VERSION 5.7 ;
  NOWIREEXTENSIONATPIN ON ;
  DIVIDERCHAR "/" ;
  BUSBITCHARS "[]" ;
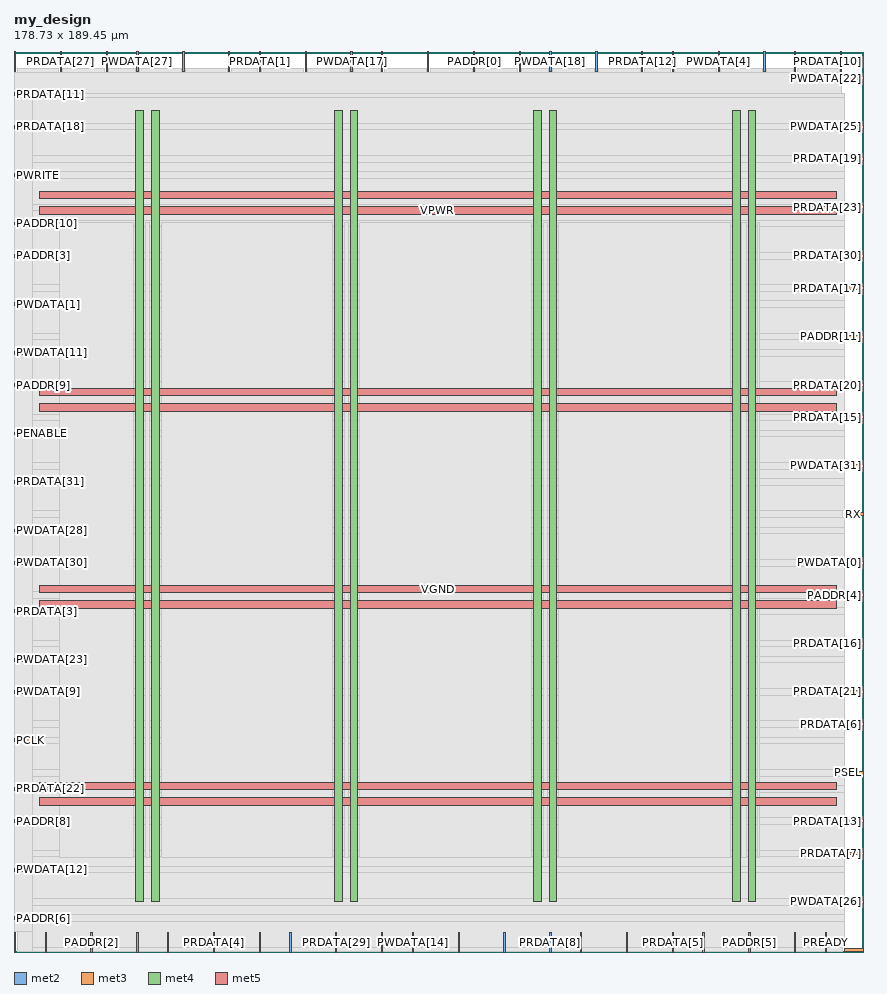
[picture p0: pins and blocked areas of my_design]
MACRO my_design
  CLASS BLOCK ;
  FOREIGN my_design ;
  ORIGIN 0.000 0.000 ;
  SIZE 178.730 BY 189.450 ;
  PIN PADDR[0]
    DIRECTION INPUT ;
    USE SIGNAL ;
    ANTENNAGATEAREA 0.196500 ;
    PORT
      LAYER met2 ;
        RECT 96.690 185.450 96.970 189.450 ;
    END
  END PADDR[0]
  PIN PADDR[10]
    DIRECTION INPUT ;
    USE SIGNAL ;
    ANTENNAGATEAREA 0.196500 ;
    PORT
      LAYER met3 ;
        RECT 0.000 153.040 4.000 153.640 ;
    END
  END PADDR[10]
  PIN PADDR[11]
    DIRECTION INPUT ;
    USE SIGNAL ;
    ANTENNAGATEAREA 0.126000 ;
    PORT
      LAYER met3 ;
        RECT 174.730 129.240 178.730 129.840 ;
    END
  END PADDR[11]
  PIN PADDR[1]
    DIRECTION INPUT ;
    USE SIGNAL ;
    ANTENNAGATEAREA 0.196500 ;
    PORT
      LAYER met2 ;
        RECT 35.510 185.450 35.790 189.450 ;
    END
  END PADDR[1]
  PIN PADDR[2]
    DIRECTION INPUT ;
    USE SIGNAL ;
    ANTENNAGATEAREA 0.159000 ;
    PORT
      LAYER met2 ;
        RECT 16.190 0.000 16.470 4.000 ;
    END
  END PADDR[2]
  PIN PADDR[3]
    DIRECTION INPUT ;
    USE SIGNAL ;
    ANTENNAGATEAREA 0.213000 ;
    PORT
      LAYER met3 ;
        RECT 0.000 146.240 4.000 146.840 ;
    END
  END PADDR[3]
  PIN PADDR[4]
    DIRECTION INPUT ;
    USE SIGNAL ;
    ANTENNAGATEAREA 0.196500 ;
    PORT
      LAYER met3 ;
        RECT 174.730 74.840 178.730 75.440 ;
    END
  END PADDR[4]
  PIN PADDR[5]
    DIRECTION INPUT ;
    USE SIGNAL ;
    ANTENNAGATEAREA 0.196500 ;
    PORT
      LAYER met2 ;
        RECT 154.650 0.000 154.930 4.000 ;
    END
  END PADDR[5]
  PIN PADDR[6]
    DIRECTION INPUT ;
    USE SIGNAL ;
    ANTENNAGATEAREA 0.196500 ;
    PORT
      LAYER met3 ;
        RECT 0.000 6.840 4.000 7.440 ;
    END
  END PADDR[6]
  PIN PADDR[7]
    DIRECTION INPUT ;
    USE SIGNAL ;
    ANTENNAGATEAREA 0.196500 ;
    PORT
      LAYER met2 ;
        RECT 144.990 0.000 145.270 4.000 ;
    END
  END PADDR[7]
  PIN PADDR[8]
    DIRECTION INPUT ;
    USE SIGNAL ;
    ANTENNAGATEAREA 0.196500 ;
    PORT
      LAYER met3 ;
        RECT 0.000 27.240 4.000 27.840 ;
    END
  END PADDR[8]
  PIN PADDR[9]
    DIRECTION INPUT ;
    USE SIGNAL ;
    ANTENNAGATEAREA 0.196500 ;
    PORT
      LAYER met3 ;
        RECT 0.000 119.040 4.000 119.640 ;
    END
  END PADDR[9]
  PIN PCLK
    DIRECTION INPUT ;
    USE SIGNAL ;
    ANTENNAGATEAREA 0.852000 ;
    PORT
      LAYER met3 ;
        RECT 0.000 44.240 4.000 44.840 ;
    END
  END PCLK
  PIN PENABLE
    DIRECTION INPUT ;
    USE SIGNAL ;
    ANTENNAGATEAREA 0.196500 ;
    PORT
      LAYER met3 ;
        RECT 0.000 108.840 4.000 109.440 ;
    END
  END PENABLE
  PIN PRDATA[0]
    DIRECTION OUTPUT TRISTATE ;
    USE SIGNAL ;
    ANTENNADIFFAREA 0.795200 ;
    PORT
      LAYER met3 ;
        RECT 174.730 0.040 178.730 0.640 ;
    END
  END PRDATA[0]
  PIN PRDATA[10]
    DIRECTION OUTPUT TRISTATE ;
    USE SIGNAL ;
    ANTENNADIFFAREA 0.795200 ;
    PORT
      LAYER met2 ;
        RECT 173.970 185.450 174.250 189.450 ;
    END
  END PRDATA[10]
  PIN PRDATA[11]
    DIRECTION OUTPUT TRISTATE ;
    USE SIGNAL ;
    ANTENNADIFFAREA 0.795200 ;
    PORT
      LAYER met3 ;
        RECT 0.000 180.240 4.000 180.840 ;
    END
  END PRDATA[11]
  PIN PRDATA[12]
    DIRECTION OUTPUT TRISTATE ;
    USE SIGNAL ;
    ANTENNADIFFAREA 0.795200 ;
    PORT
      LAYER met2 ;
        RECT 132.110 185.450 132.390 189.450 ;
    END
  END PRDATA[12]
  PIN PRDATA[13]
    DIRECTION OUTPUT TRISTATE ;
    USE SIGNAL ;
    ANTENNADIFFAREA 0.795200 ;
    PORT
      LAYER met3 ;
        RECT 174.730 27.240 178.730 27.840 ;
    END
  END PRDATA[13]
  PIN PRDATA[14]
    DIRECTION OUTPUT TRISTATE ;
    USE SIGNAL ;
    ANTENNADIFFAREA 0.795200 ;
    PORT
      LAYER met2 ;
        RECT 87.030 185.450 87.310 189.450 ;
    END
  END PRDATA[14]
  PIN PRDATA[15]
    DIRECTION OUTPUT TRISTATE ;
    USE SIGNAL ;
    ANTENNADIFFAREA 0.445500 ;
    PORT
      LAYER met3 ;
        RECT 174.730 112.240 178.730 112.840 ;
    END
  END PRDATA[15]
  PIN PRDATA[16]
    DIRECTION OUTPUT TRISTATE ;
    USE SIGNAL ;
    ANTENNADIFFAREA 0.445500 ;
    PORT
      LAYER met3 ;
        RECT 174.730 64.640 178.730 65.240 ;
    END
  END PRDATA[16]
  PIN PRDATA[17]
    DIRECTION OUTPUT TRISTATE ;
    USE SIGNAL ;
    PORT
      LAYER met3 ;
        RECT 174.730 139.440 178.730 140.040 ;
    END
  END PRDATA[17]
  PIN PRDATA[18]
    DIRECTION OUTPUT TRISTATE ;
    USE SIGNAL ;
    ANTENNADIFFAREA 0.795200 ;
    PORT
      LAYER met3 ;
        RECT 0.000 173.440 4.000 174.040 ;
    END
  END PRDATA[18]
  PIN PRDATA[19]
    DIRECTION OUTPUT TRISTATE ;
    USE SIGNAL ;
    ANTENNADIFFAREA 0.445500 ;
    PORT
      LAYER met3 ;
        RECT 174.730 166.640 178.730 167.240 ;
    END
  END PRDATA[19]
  PIN PRDATA[1]
    DIRECTION OUTPUT TRISTATE ;
    USE SIGNAL ;
    ANTENNADIFFAREA 0.795200 ;
    PORT
      LAYER met2 ;
        RECT 51.610 185.450 51.890 189.450 ;
    END
  END PRDATA[1]
  PIN PRDATA[20]
    DIRECTION OUTPUT TRISTATE ;
    USE SIGNAL ;
    PORT
      LAYER met3 ;
        RECT 174.730 119.040 178.730 119.640 ;
    END
  END PRDATA[20]
  PIN PRDATA[21]
    DIRECTION OUTPUT TRISTATE ;
    USE SIGNAL ;
    ANTENNADIFFAREA 0.795200 ;
    PORT
      LAYER met3 ;
        RECT 174.730 54.440 178.730 55.040 ;
    END
  END PRDATA[21]
  PIN PRDATA[22]
    DIRECTION OUTPUT TRISTATE ;
    USE SIGNAL ;
    PORT
      LAYER met3 ;
        RECT 0.000 34.040 4.000 34.640 ;
    END
  END PRDATA[22]
  PIN PRDATA[23]
    DIRECTION OUTPUT TRISTATE ;
    USE SIGNAL ;
    ANTENNADIFFAREA 0.795200 ;
    PORT
      LAYER met3 ;
        RECT 174.730 156.440 178.730 157.040 ;
    END
  END PRDATA[23]
  PIN PRDATA[24]
    DIRECTION OUTPUT TRISTATE ;
    USE SIGNAL ;
    PORT
      LAYER met2 ;
        RECT 51.610 0.000 51.890 4.000 ;
    END
  END PRDATA[24]
  PIN PRDATA[25]
    DIRECTION OUTPUT TRISTATE ;
    USE SIGNAL ;
    ANTENNADIFFAREA 0.795200 ;
    PORT
      LAYER met2 ;
        RECT 164.310 0.000 164.590 4.000 ;
    END
  END PRDATA[25]
  PIN PRDATA[26]
    DIRECTION OUTPUT TRISTATE ;
    USE SIGNAL ;
    ANTENNADIFFAREA 0.795200 ;
    PORT
      LAYER met2 ;
        RECT 122.450 185.450 122.730 189.450 ;
    END
  END PRDATA[26]
  PIN PRDATA[27]
    DIRECTION OUTPUT TRISTATE ;
    USE SIGNAL ;
    ANTENNADIFFAREA 0.795200 ;
    PORT
      LAYER met2 ;
        RECT 9.750 185.450 10.030 189.450 ;
    END
  END PRDATA[27]
  PIN PRDATA[28]
    DIRECTION OUTPUT TRISTATE ;
    USE SIGNAL ;
    ANTENNADIFFAREA 0.795200 ;
    PORT
      LAYER met2 ;
        RECT 106.350 185.450 106.630 189.450 ;
    END
  END PRDATA[28]
  PIN PRDATA[29]
    DIRECTION OUTPUT TRISTATE ;
    USE SIGNAL ;
    PORT
      LAYER met2 ;
        RECT 67.710 0.000 67.990 4.000 ;
    END
  END PRDATA[29]
  PIN PRDATA[2]
    DIRECTION OUTPUT TRISTATE ;
    USE SIGNAL ;
    ANTENNADIFFAREA 0.795200 ;
    PORT
      LAYER met2 ;
        RECT 157.870 185.450 158.150 189.450 ;
    END
  END PRDATA[2]
  PIN PRDATA[30]
    DIRECTION OUTPUT TRISTATE ;
    USE SIGNAL ;
    ANTENNADIFFAREA 0.445500 ;
    PORT
      LAYER met3 ;
        RECT 174.730 146.240 178.730 146.840 ;
    END
  END PRDATA[30]
  PIN PRDATA[31]
    DIRECTION OUTPUT TRISTATE ;
    USE SIGNAL ;
    ANTENNADIFFAREA 0.795200 ;
    PORT
      LAYER met3 ;
        RECT 0.000 98.640 4.000 99.240 ;
    END
  END PRDATA[31]
  PIN PRDATA[3]
    DIRECTION OUTPUT TRISTATE ;
    USE SIGNAL ;
    ANTENNADIFFAREA 0.795200 ;
    PORT
      LAYER met3 ;
        RECT 0.000 71.440 4.000 72.040 ;
    END
  END PRDATA[3]
  PIN PRDATA[4]
    DIRECTION OUTPUT TRISTATE ;
    USE SIGNAL ;
    ANTENNADIFFAREA 0.795200 ;
    PORT
      LAYER met2 ;
        RECT 41.950 0.000 42.230 4.000 ;
    END
  END PRDATA[4]
  PIN PRDATA[5]
    DIRECTION OUTPUT TRISTATE ;
    USE SIGNAL ;
    ANTENNADIFFAREA 0.795200 ;
    PORT
      LAYER met2 ;
        RECT 138.550 0.000 138.830 4.000 ;
    END
  END PRDATA[5]
  PIN PRDATA[6]
    DIRECTION OUTPUT TRISTATE ;
    USE SIGNAL ;
    ANTENNADIFFAREA 0.795200 ;
    PORT
      LAYER met3 ;
        RECT 174.730 47.640 178.730 48.240 ;
    END
  END PRDATA[6]
  PIN PRDATA[7]
    DIRECTION OUTPUT TRISTATE ;
    USE SIGNAL ;
    ANTENNADIFFAREA 0.795200 ;
    PORT
      LAYER met3 ;
        RECT 174.730 20.440 178.730 21.040 ;
    END
  END PRDATA[7]
  PIN PRDATA[8]
    DIRECTION OUTPUT TRISTATE ;
    USE SIGNAL ;
    ANTENNADIFFAREA 0.795200 ;
    PORT
      LAYER met2 ;
        RECT 112.790 0.000 113.070 4.000 ;
    END
  END PRDATA[8]
  PIN PRDATA[9]
    DIRECTION OUTPUT TRISTATE ;
    USE SIGNAL ;
    ANTENNADIFFAREA 0.795200 ;
    PORT
      LAYER met2 ;
        RECT 0.090 185.450 0.370 189.450 ;
    END
  END PRDATA[9]
  PIN PREADY
    DIRECTION OUTPUT TRISTATE ;
    USE SIGNAL ;
    ANTENNADIFFAREA 0.795200 ;
    PORT
      LAYER met2 ;
        RECT 170.750 0.000 171.030 4.000 ;
    END
  END PREADY
  PIN PRESETn
    DIRECTION INPUT ;
    USE SIGNAL ;
    ANTENNAGATEAREA 0.196500 ;
    PORT
      LAYER met2 ;
        RECT 61.270 185.450 61.550 189.450 ;
    END
  END PRESETn
  PIN PSEL
    DIRECTION INPUT ;
    USE SIGNAL ;
    ANTENNAGATEAREA 0.159000 ;
    PORT
      LAYER met3 ;
        RECT 174.730 37.440 178.730 38.040 ;
    END
  END PSEL
  PIN PWDATA[0]
    DIRECTION INPUT ;
    USE SIGNAL ;
    ANTENNAGATEAREA 0.213000 ;
    PORT
      LAYER met3 ;
        RECT 174.730 81.640 178.730 82.240 ;
    END
  END PWDATA[0]
  PIN PWDATA[10]
    DIRECTION INPUT ;
    USE SIGNAL ;
    ANTENNAGATEAREA 0.126000 ;
    PORT
      LAYER met2 ;
        RECT 128.890 0.000 129.170 4.000 ;
    END
  END PWDATA[10]
  PIN PWDATA[11]
    DIRECTION INPUT ;
    USE SIGNAL ;
    ANTENNAGATEAREA 0.196500 ;
    PORT
      LAYER met3 ;
        RECT 0.000 125.840 4.000 126.440 ;
    END
  END PWDATA[11]
  PIN PWDATA[12]
    DIRECTION INPUT ;
    USE SIGNAL ;
    ANTENNAGATEAREA 0.196500 ;
    PORT
      LAYER met3 ;
        RECT 0.000 17.040 4.000 17.640 ;
    END
  END PWDATA[12]
  PIN PWDATA[13]
    DIRECTION INPUT ;
    USE SIGNAL ;
    ANTENNAGATEAREA 0.196500 ;
    PORT
      LAYER met2 ;
        RECT 77.370 185.450 77.650 189.450 ;
    END
  END PWDATA[13]
  PIN PWDATA[14]
    DIRECTION INPUT ;
    USE SIGNAL ;
    ANTENNAGATEAREA 0.196500 ;
    PORT
      LAYER met2 ;
        RECT 83.810 0.000 84.090 4.000 ;
    END
  END PWDATA[14]
  PIN PWDATA[15]
    DIRECTION INPUT ;
    USE SIGNAL ;
    ANTENNAGATEAREA 0.196500 ;
    PORT
      LAYER met2 ;
        RECT 0.090 0.000 0.370 4.000 ;
    END
  END PWDATA[15]
  PIN PWDATA[16]
    DIRECTION INPUT ;
    USE SIGNAL ;
    PORT
      LAYER met2 ;
        RECT 103.130 0.000 103.410 4.000 ;
    END
  END PWDATA[16]
  PIN PWDATA[17]
    DIRECTION INPUT ;
    USE SIGNAL ;
    PORT
      LAYER met2 ;
        RECT 70.930 185.450 71.210 189.450 ;
    END
  END PWDATA[17]
  PIN PWDATA[18]
    DIRECTION INPUT ;
    USE SIGNAL ;
    PORT
      LAYER met2 ;
        RECT 112.790 185.450 113.070 189.450 ;
    END
  END PWDATA[18]
  PIN PWDATA[19]
    DIRECTION INPUT ;
    USE SIGNAL ;
    PORT
      LAYER met2 ;
        RECT 164.310 185.450 164.590 189.450 ;
    END
  END PWDATA[19]
  PIN PWDATA[1]
    DIRECTION INPUT ;
    USE SIGNAL ;
    ANTENNAGATEAREA 0.196500 ;
    PORT
      LAYER met3 ;
        RECT 0.000 136.040 4.000 136.640 ;
    END
  END PWDATA[1]
  PIN PWDATA[20]
    DIRECTION INPUT ;
    USE SIGNAL ;
    PORT
      LAYER met2 ;
        RECT 25.850 0.000 26.130 4.000 ;
    END
  END PWDATA[20]
  PIN PWDATA[21]
    DIRECTION INPUT ;
    USE SIGNAL ;
    PORT
      LAYER met2 ;
        RECT 6.530 0.000 6.810 4.000 ;
    END
  END PWDATA[21]
  PIN PWDATA[22]
    DIRECTION INPUT ;
    USE SIGNAL ;
    PORT
      LAYER met3 ;
        RECT 174.730 183.640 178.730 184.240 ;
    END
  END PWDATA[22]
  PIN PWDATA[23]
    DIRECTION INPUT ;
    USE SIGNAL ;
    PORT
      LAYER met3 ;
        RECT 0.000 61.240 4.000 61.840 ;
    END
  END PWDATA[23]
  PIN PWDATA[24]
    DIRECTION INPUT ;
    USE SIGNAL ;
    PORT
      LAYER met2 ;
        RECT 77.370 0.000 77.650 4.000 ;
    END
  END PWDATA[24]
  PIN PWDATA[25]
    DIRECTION INPUT ;
    USE SIGNAL ;
    PORT
      LAYER met3 ;
        RECT 174.730 173.440 178.730 174.040 ;
    END
  END PWDATA[25]
  PIN PWDATA[26]
    DIRECTION INPUT ;
    USE SIGNAL ;
    PORT
      LAYER met3 ;
        RECT 174.730 10.240 178.730 10.840 ;
    END
  END PWDATA[26]
  PIN PWDATA[27]
    DIRECTION INPUT ;
    USE SIGNAL ;
    PORT
      LAYER met2 ;
        RECT 25.850 185.450 26.130 189.450 ;
    END
  END PWDATA[27]
  PIN PWDATA[28]
    DIRECTION INPUT ;
    USE SIGNAL ;
    PORT
      LAYER met3 ;
        RECT 0.000 88.440 4.000 89.040 ;
    END
  END PWDATA[28]
  PIN PWDATA[29]
    DIRECTION INPUT ;
    USE SIGNAL ;
    PORT
      LAYER met2 ;
        RECT 32.290 0.000 32.570 4.000 ;
    END
  END PWDATA[29]
  PIN PWDATA[2]
    DIRECTION INPUT ;
    USE SIGNAL ;
    ANTENNAGATEAREA 0.196500 ;
    PORT
      LAYER met2 ;
        RECT 58.050 0.000 58.330 4.000 ;
    END
  END PWDATA[2]
  PIN PWDATA[30]
    DIRECTION INPUT ;
    USE SIGNAL ;
    PORT
      LAYER met3 ;
        RECT 0.000 81.640 4.000 82.240 ;
    END
  END PWDATA[30]
  PIN PWDATA[31]
    DIRECTION INPUT ;
    USE SIGNAL ;
    PORT
      LAYER met3 ;
        RECT 174.730 102.040 178.730 102.640 ;
    END
  END PWDATA[31]
  PIN PWDATA[3]
    DIRECTION INPUT ;
    USE SIGNAL ;
    ANTENNAGATEAREA 0.196500 ;
    PORT
      LAYER met2 ;
        RECT 93.470 0.000 93.750 4.000 ;
    END
  END PWDATA[3]
  PIN PWDATA[4]
    DIRECTION INPUT ;
    USE SIGNAL ;
    ANTENNAGATEAREA 0.196500 ;
    PORT
      LAYER met2 ;
        RECT 148.210 185.450 148.490 189.450 ;
    END
  END PWDATA[4]
  PIN PWDATA[5]
    DIRECTION INPUT ;
    USE SIGNAL ;
    ANTENNAGATEAREA 0.196500 ;
    PORT
      LAYER met2 ;
        RECT 138.550 185.450 138.830 189.450 ;
    END
  END PWDATA[5]
  PIN PWDATA[6]
    DIRECTION INPUT ;
    USE SIGNAL ;
    ANTENNAGATEAREA 0.196500 ;
    PORT
      LAYER met2 ;
        RECT 19.410 185.450 19.690 189.450 ;
    END
  END PWDATA[6]
  PIN PWDATA[7]
    DIRECTION INPUT ;
    USE SIGNAL ;
    ANTENNAGATEAREA 0.196500 ;
    PORT
      LAYER met2 ;
        RECT 45.170 185.450 45.450 189.450 ;
    END
  END PWDATA[7]
  PIN PWDATA[8]
    DIRECTION INPUT ;
    USE SIGNAL ;
    ANTENNAGATEAREA 0.196500 ;
    PORT
      LAYER met2 ;
        RECT 119.230 0.000 119.510 4.000 ;
    END
  END PWDATA[8]
  PIN PWDATA[9]
    DIRECTION INPUT ;
    USE SIGNAL ;
    ANTENNAGATEAREA 0.196500 ;
    PORT
      LAYER met3 ;
        RECT 0.000 54.440 4.000 55.040 ;
    END
  END PWDATA[9]
  PIN PWRITE
    DIRECTION INPUT ;
    USE SIGNAL ;
    ANTENNAGATEAREA 0.126000 ;
    PORT
      LAYER met3 ;
        RECT 0.000 163.240 4.000 163.840 ;
    END
  END PWRITE
  PIN RX
    DIRECTION INPUT ;
    USE SIGNAL ;
    ANTENNAGATEAREA 0.196500 ;
    PORT
      LAYER met3 ;
        RECT 174.730 91.840 178.730 92.440 ;
    END
  END RX
  PIN VGND
    DIRECTION INOUT ;
    USE GROUND ;
    PORT
      LAYER met4 ;
        RECT 28.950 10.640 30.550 177.040 ;
    END
    PORT
      LAYER met4 ;
        RECT 70.810 10.640 72.410 177.040 ;
    END
    PORT
      LAYER met4 ;
        RECT 112.670 10.640 114.270 177.040 ;
    END
    PORT
      LAYER met4 ;
        RECT 154.530 10.640 156.130 177.040 ;
    END
    PORT
      LAYER met5 ;
        RECT 5.280 34.120 173.200 35.720 ;
    END
    PORT
      LAYER met5 ;
        RECT 5.280 75.600 173.200 77.200 ;
    END
    PORT
      LAYER met5 ;
        RECT 5.280 117.080 173.200 118.680 ;
    END
    PORT
      LAYER met5 ;
        RECT 5.280 158.560 173.200 160.160 ;
    END
  END VGND
  PIN VPWR
    DIRECTION INOUT ;
    USE POWER ;
    PORT
      LAYER met4 ;
        RECT 25.650 10.640 27.250 177.040 ;
    END
    PORT
      LAYER met4 ;
        RECT 67.510 10.640 69.110 177.040 ;
    END
    PORT
      LAYER met4 ;
        RECT 109.370 10.640 110.970 177.040 ;
    END
    PORT
      LAYER met4 ;
        RECT 151.230 10.640 152.830 177.040 ;
    END
    PORT
      LAYER met5 ;
        RECT 5.280 30.820 173.200 32.420 ;
    END
    PORT
      LAYER met5 ;
        RECT 5.280 72.300 173.200 73.900 ;
    END
    PORT
      LAYER met5 ;
        RECT 5.280 113.780 173.200 115.380 ;
    END
    PORT
      LAYER met5 ;
        RECT 5.280 155.260 173.200 156.860 ;
    END
  END VPWR
  OBS
      LAYER li1 ;
        RECT 5.520 10.795 172.960 176.885 ;
      LAYER met1 ;
        RECT 0.070 9.220 174.270 177.040 ;
      LAYER met2 ;
        RECT 0.650 185.170 9.470 186.050 ;
        RECT 10.310 185.170 19.130 186.050 ;
        RECT 19.970 185.170 25.570 186.050 ;
        RECT 26.410 185.170 35.230 186.050 ;
        RECT 36.070 185.170 44.890 186.050 ;
        RECT 45.730 185.170 51.330 186.050 ;
        RECT 52.170 185.170 60.990 186.050 ;
        RECT 61.830 185.170 70.650 186.050 ;
        RECT 71.490 185.170 77.090 186.050 ;
        RECT 77.930 185.170 86.750 186.050 ;
        RECT 87.590 185.170 96.410 186.050 ;
        RECT 97.250 185.170 106.070 186.050 ;
        RECT 106.910 185.170 112.510 186.050 ;
        RECT 113.350 185.170 122.170 186.050 ;
        RECT 123.010 185.170 131.830 186.050 ;
        RECT 132.670 185.170 138.270 186.050 ;
        RECT 139.110 185.170 147.930 186.050 ;
        RECT 148.770 185.170 157.590 186.050 ;
        RECT 158.430 185.170 164.030 186.050 ;
        RECT 164.870 185.170 173.690 186.050 ;
        RECT 0.100 4.280 174.250 185.170 ;
        RECT 0.650 0.155 6.250 4.280 ;
        RECT 7.090 0.155 15.910 4.280 ;
        RECT 16.750 0.155 25.570 4.280 ;
        RECT 26.410 0.155 32.010 4.280 ;
        RECT 32.850 0.155 41.670 4.280 ;
        RECT 42.510 0.155 51.330 4.280 ;
        RECT 52.170 0.155 57.770 4.280 ;
        RECT 58.610 0.155 67.430 4.280 ;
        RECT 68.270 0.155 77.090 4.280 ;
        RECT 77.930 0.155 83.530 4.280 ;
        RECT 84.370 0.155 93.190 4.280 ;
        RECT 94.030 0.155 102.850 4.280 ;
        RECT 103.690 0.155 112.510 4.280 ;
        RECT 113.350 0.155 118.950 4.280 ;
        RECT 119.790 0.155 128.610 4.280 ;
        RECT 129.450 0.155 138.270 4.280 ;
        RECT 139.110 0.155 144.710 4.280 ;
        RECT 145.550 0.155 154.370 4.280 ;
        RECT 155.210 0.155 164.030 4.280 ;
        RECT 164.870 0.155 170.470 4.280 ;
        RECT 171.310 0.155 174.250 4.280 ;
      LAYER met3 ;
        RECT 4.400 179.840 174.730 180.690 ;
        RECT 3.990 174.440 174.730 179.840 ;
        RECT 4.400 173.040 174.330 174.440 ;
        RECT 3.990 167.640 174.730 173.040 ;
        RECT 3.990 166.240 174.330 167.640 ;
        RECT 3.990 164.240 174.730 166.240 ;
        RECT 4.400 162.840 174.730 164.240 ;
        RECT 3.990 157.440 174.730 162.840 ;
        RECT 3.990 156.040 174.330 157.440 ;
        RECT 3.990 154.040 174.730 156.040 ;
        RECT 4.400 152.640 174.730 154.040 ;
        RECT 3.990 147.240 174.730 152.640 ;
        RECT 4.400 145.840 174.330 147.240 ;
        RECT 3.990 140.440 174.730 145.840 ;
        RECT 3.990 139.040 174.330 140.440 ;
        RECT 3.990 137.040 174.730 139.040 ;
        RECT 4.400 135.640 174.730 137.040 ;
        RECT 3.990 130.240 174.730 135.640 ;
        RECT 3.990 128.840 174.330 130.240 ;
        RECT 3.990 126.840 174.730 128.840 ;
        RECT 4.400 125.440 174.730 126.840 ;
        RECT 3.990 120.040 174.730 125.440 ;
        RECT 4.400 118.640 174.330 120.040 ;
        RECT 3.990 113.240 174.730 118.640 ;
        RECT 3.990 111.840 174.330 113.240 ;
        RECT 3.990 109.840 174.730 111.840 ;
        RECT 4.400 108.440 174.730 109.840 ;
        RECT 3.990 103.040 174.730 108.440 ;
        RECT 3.990 101.640 174.330 103.040 ;
        RECT 3.990 99.640 174.730 101.640 ;
        RECT 4.400 98.240 174.730 99.640 ;
        RECT 3.990 92.840 174.730 98.240 ;
        RECT 3.990 91.440 174.330 92.840 ;
        RECT 3.990 89.440 174.730 91.440 ;
        RECT 4.400 88.040 174.730 89.440 ;
        RECT 3.990 82.640 174.730 88.040 ;
        RECT 4.400 81.240 174.330 82.640 ;
        RECT 3.990 75.840 174.730 81.240 ;
        RECT 3.990 74.440 174.330 75.840 ;
        RECT 3.990 72.440 174.730 74.440 ;
        RECT 4.400 71.040 174.730 72.440 ;
        RECT 3.990 65.640 174.730 71.040 ;
        RECT 3.990 64.240 174.330 65.640 ;
        RECT 3.990 62.240 174.730 64.240 ;
        RECT 4.400 60.840 174.730 62.240 ;
        RECT 3.990 55.440 174.730 60.840 ;
        RECT 4.400 54.040 174.330 55.440 ;
        RECT 3.990 48.640 174.730 54.040 ;
        RECT 3.990 47.240 174.330 48.640 ;
        RECT 3.990 45.240 174.730 47.240 ;
        RECT 4.400 43.840 174.730 45.240 ;
        RECT 3.990 38.440 174.730 43.840 ;
        RECT 3.990 37.040 174.330 38.440 ;
        RECT 3.990 35.040 174.730 37.040 ;
        RECT 4.400 33.640 174.730 35.040 ;
        RECT 3.990 28.240 174.730 33.640 ;
        RECT 4.400 26.840 174.330 28.240 ;
        RECT 3.990 21.440 174.730 26.840 ;
        RECT 3.990 20.040 174.330 21.440 ;
        RECT 3.990 18.040 174.730 20.040 ;
        RECT 4.400 16.640 174.730 18.040 ;
        RECT 3.990 11.240 174.730 16.640 ;
        RECT 3.990 9.840 174.330 11.240 ;
        RECT 3.990 7.840 174.730 9.840 ;
        RECT 4.400 6.440 174.730 7.840 ;
        RECT 3.990 1.040 174.730 6.440 ;
        RECT 3.990 0.175 174.330 1.040 ;
      LAYER met4 ;
        RECT 9.495 19.895 25.250 153.505 ;
        RECT 27.650 19.895 28.550 153.505 ;
        RECT 30.950 19.895 67.110 153.505 ;
        RECT 69.510 19.895 70.410 153.505 ;
        RECT 72.810 19.895 108.970 153.505 ;
        RECT 111.370 19.895 112.270 153.505 ;
        RECT 114.670 19.895 150.830 153.505 ;
        RECT 153.230 19.895 154.130 153.505 ;
        RECT 156.530 19.895 157.025 153.505 ;
  END
END my_design
END LIBRARY

